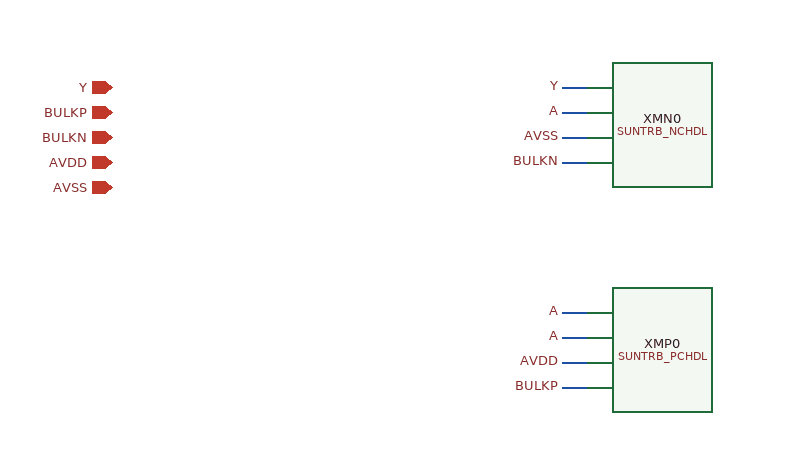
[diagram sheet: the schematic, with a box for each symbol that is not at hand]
v {xschem version=3.0.0 file_version=1.2 }
G {}
K {}
V {}
S {}
E {}
C {devices/iopin.sym} 0 0 0 0{name=p0 lab=Y}
C {devices/ipin.sym} 0 20 0 0{name=p1 lab=BULKP}
C {devices/ipin.sym} 0 40 0 0{name=p2 lab=BULKN}
C {devices/iopin.sym} 0 60 0 0{name=p3 lab=AVDD}
C {devices/iopin.sym} 0 80 0 0{name=p4 lab=AVSS}
C {SUN_TRB_SKY130NM/SUNTRB_NCHDL.sym} 400 0 0 0 {name=XMN0}
N 360.0 0.0 380.0 0.0{lab=Y}
C {devices/lab_pin.sym} 360.0 0.0 0 0  {name=l0 sig_type=std_logic lab=Y }
N 360.0 20.0 380.0 20.0{lab=A}
C {devices/lab_pin.sym} 360.0 20.0 0 0  {name=l1 sig_type=std_logic lab=A }
N 360.0 40.0 380.0 40.0{lab=AVSS}
C {devices/lab_pin.sym} 360.0 40.0 0 0  {name=l2 sig_type=std_logic lab=AVSS }
N 360.0 60.0 380.0 60.0{lab=BULKN}
C {devices/lab_pin.sym} 360.0 60.0 0 0  {name=l3 sig_type=std_logic lab=BULKN }
C {SUN_TRB_SKY130NM/SUNTRB_PCHDL.sym} 400 180.0 0 0 {name=XMP0}
N 360.0 180.0 380.0 180.0{lab=A}
C {devices/lab_pin.sym} 360.0 180.0 0 0  {name=l4 sig_type=std_logic lab=A }
N 360.0 200.0 380.0 200.0{lab=A}
C {devices/lab_pin.sym} 360.0 200.0 0 0  {name=l5 sig_type=std_logic lab=A }
N 360.0 220.0 380.0 220.0{lab=AVDD}
C {devices/lab_pin.sym} 360.0 220.0 0 0  {name=l6 sig_type=std_logic lab=AVDD }
N 360.0 240.0 380.0 240.0{lab=BULKP}
C {devices/lab_pin.sym} 360.0 240.0 0 0  {name=l7 sig_type=std_logic lab=BULKP }
